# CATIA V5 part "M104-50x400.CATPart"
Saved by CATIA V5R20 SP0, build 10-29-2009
Part number: M104-50x400
Source: Unknown
Bounding box of the stored display mesh (mm): x -24.865 to 24.865, y -24.997 to 24.997, z 0 to 400
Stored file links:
  C:\Users\Utente\Desktop\IO LAVORO\3D X SITO CF\X SITO\M104\M104-50x400.CATPart

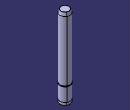
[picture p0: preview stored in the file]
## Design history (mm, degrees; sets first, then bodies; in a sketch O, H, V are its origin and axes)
Body1 (main body)
  Solid1 "PartBody": solid without history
